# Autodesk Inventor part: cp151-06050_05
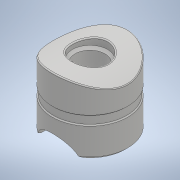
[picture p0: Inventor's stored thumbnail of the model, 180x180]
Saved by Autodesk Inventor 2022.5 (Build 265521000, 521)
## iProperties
Part Number: cp151-06050_05
Material: 一般
Document SubType Name: Modeling
Designer: ImaoCorp
Density: 1 g/cm^3
Appearance: 既定
Author: ImaoCorp
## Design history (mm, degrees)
feature "cp151-06050_05"
node "ソリッド1"
